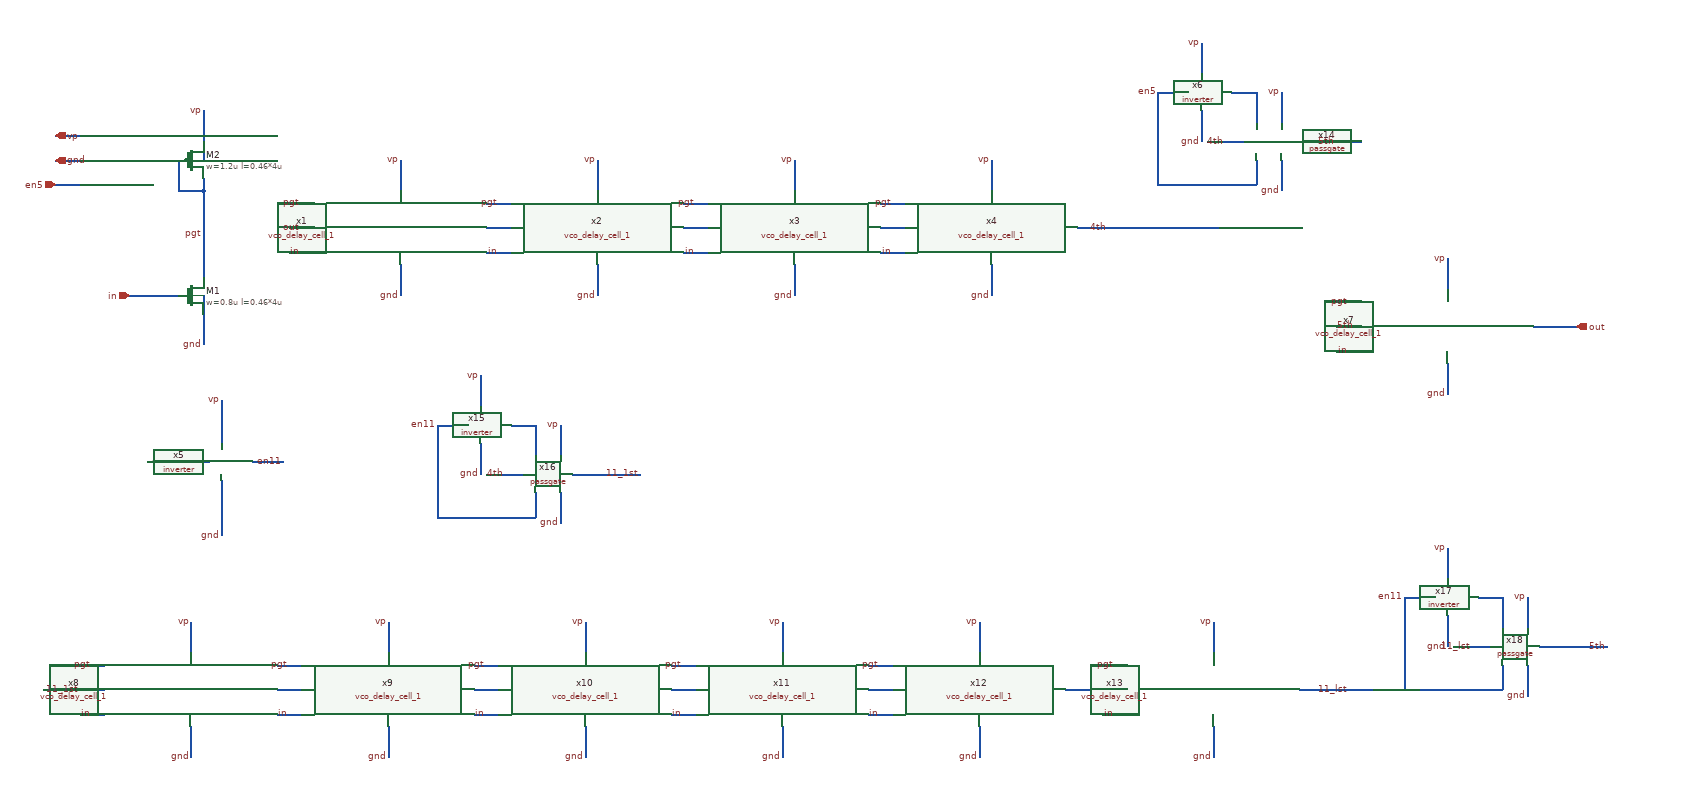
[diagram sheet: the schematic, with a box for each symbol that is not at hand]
v {xschem version=3.4.8RC file_version=1.3}
G {}
K {}
V {}
S {}
F {}
E {}
N -330 -360 -250 -360 {lab=in}
N -250 -530 -210 -530 {lab=pgt}
N -210 -530 -210 -390 {lab=pgt}
N -70 -470 -30 -470 {lab=out}
N -70 -510 -30 -510 {lab=pgt}
N -70 -430 -30 -430 {lab=in}
N 110 -580 110 -530 {lab=vp}
N 110 -410 110 -360 {lab=gnd}
N 250 -510 290 -510 {lab=pgt}
N 250 -430 290 -430 {lab=in}
N 430 -580 430 -530 {lab=vp}
N 430 -410 430 -360 {lab=gnd}
N 570 -510 610 -510 {lab=pgt}
N 570 -430 610 -430 {lab=in}
N 750 -580 750 -530 {lab=vp}
N 750 -410 750 -360 {lab=gnd}
N 890 -510 930 -510 {lab=pgt}
N 890 -430 930 -430 {lab=in}
N 1070 -580 1070 -530 {lab=vp}
N 1070 -410 1070 -360 {lab=gnd}
N -450 -620 -410 -620 {lab=vp}
N -450 -580 -410 -580 {lab=gnd}
N -210 -360 -210 -280 {lab=gnd}
N -250 -580 -250 -530 {lab=pgt}
N -210 -550 -210 -530 {lab=pgt}
N -210 -660 -210 -580 {lab=vp}
N 250 -470 290 -470 {lab=#net1}
N 570 -470 610 -470 {lab=#net2}
N 890 -470 930 -470 {lab=#net3}
N 1630 -350 1670 -350 {lab=pgt}
N 1630 -270 1670 -270 {lab=in}
N 1810 -420 1810 -370 {lab=vp}
N 1810 -250 1810 -200 {lab=gnd}
N 1630 -310 1670 -310 {lab=5th}
N 1950 -310 2020 -310 {lab=out}
N -410 240 -370 240 {lab=pgt}
N -410 320 -370 320 {lab=in}
N -230 170 -230 220 {lab=vp}
N -230 340 -230 390 {lab=gnd}
N -90 240 -50 240 {lab=pgt}
N -90 320 -50 320 {lab=in}
N 90 170 90 220 {lab=vp}
N 90 340 90 390 {lab=gnd}
N 230 240 270 240 {lab=pgt}
N 230 320 270 320 {lab=in}
N 410 170 410 220 {lab=vp}
N 410 340 410 390 {lab=gnd}
N 550 240 590 240 {lab=pgt}
N 550 320 590 320 {lab=in}
N 730 170 730 220 {lab=vp}
N 730 340 730 390 {lab=gnd}
N 870 240 910 240 {lab=pgt}
N 870 320 910 320 {lab=in}
N 1050 170 1050 220 {lab=vp}
N 1050 340 1050 390 {lab=gnd}
N -90 280 -50 280 {lab=#net4}
N 230 280 270 280 {lab=#net5}
N 550 280 590 280 {lab=#net6}
N 870 280 910 280 {lab=#net7}
N 1250 240 1290 240 {lab=pgt}
N 1250 320 1290 320 {lab=in}
N 1430 170 1430 220 {lab=vp}
N 1430 340 1430 390 {lab=gnd}
N 1190 280 1290 280 {lab=#net8}
N 1210 -470 1440 -470 {lab=4th}
N 1570 280 1690 280 {lab=11_lst}
N -470 280 -370 280 {lab=11_1st}
N -450 -540 -410 -540 {lab=en5}
N -300 -90 -200 -90 {lab=en5}
N -130 -90 -80 -90 {lab=en11}
N -180 -60 -180 30 {lab=gnd}
N -180 -190 -180 -120 {lab=vp}
N 1460 -690 1500 -690 {lab=#net9}
N 1500 -690 1500 -640 {lab=#net9}
N 1340 -690 1390 -690 {lab=en5}
N 1340 -690 1340 -540 {lab=en5}
N 1340 -540 1500 -540 {lab=en5}
N 1500 -580 1500 -540 {lab=en5}
N 1420 -610 1480 -610 {lab=4th}
N 1560 -610 1670 -610 {lab=5th}
N 1410 -770 1410 -720 {lab=vp}
N 1410 -660 1410 -610 {lab=gnd}
N 1540 -580 1540 -530 {lab=gnd}
N 1540 -690 1540 -640 {lab=vp}
N 290 -150 330 -150 {lab=#net10}
N 330 -150 330 -100 {lab=#net10}
N 170 -150 220 -150 {lab=en11}
N 170 -150 170 0 {lab=en11}
N 170 0 330 0 {lab=en11}
N 330 -40 330 0 {lab=en11}
N 250 -70 310 -70 {lab=4th}
N 390 -70 500 -70 {lab=11_1st}
N 240 -230 240 -180 {lab=vp}
N 240 -120 240 -70 {lab=gnd}
N 370 -40 370 10 {lab=gnd}
N 370 -150 370 -100 {lab=vp}
N 1860 130 1900 130 {lab=#net11}
N 1900 130 1900 180 {lab=#net11}
N 1740 130 1790 130 {lab=en11}
N 1740 130 1740 280 {lab=en11}
N 1740 280 1900 280 {lab=en11}
N 1900 240 1900 280 {lab=en11}
N 1820 210 1880 210 {lab=11_lst}
N 1960 210 2070 210 {lab=11_1st}
N 1810 50 1810 100 {lab=vp}
N 1810 160 1810 210 {lab=gnd}
N 1940 240 1940 290 {lab=gnd}
N 1940 130 1940 180 {lab=vp}
C {sg13g2_pr/sg13_lv_nmos.sym} -230 -360 0 0 {name=M1
l=0.46*4u
w=0.8u
ng=1
m=1
model=sg13_lv_nmos
spiceprefix=X
}
C {sg13g2_pr/sg13_lv_pmos.sym} -230 -580 0 0 {name=M2
l=0.46*4u
w=1.2u
ng=1
m=1
model=sg13_lv_pmos
spiceprefix=X
}
C {ipin.sym} -330 -360 0 0 {name=p1 lab=in}
C {iopin.sym} -450 -620 0 1 {name=p3 lab=vp
}
C {opin.sym} 2020 -310 0 0 {name=p4 lab=out}
C {/foss/designs/CHIP-PLL/schematics/vco/vco_cell/vco_delay_cell_1.sym} 110 -470 0 0 {name=x1}
C {lab_wire.sym} -50 -470 0 0 {name=p5 sig_type=std_logic lab=out
}
C {lab_wire.sym} -50 -510 0 0 {name=p10 sig_type=std_logic lab=pgt
}
C {lab_wire.sym} -50 -430 0 0 {name=p11 sig_type=std_logic lab=in
}
C {lab_wire.sym} -210 -660 0 0 {name=p12 sig_type=std_logic lab=vp
}
C {lab_wire.sym} 110 -580 0 0 {name=p13 sig_type=std_logic lab=vp
}
C {lab_wire.sym} 110 -360 0 0 {name=p15 sig_type=std_logic lab=gnd
}
C {/foss/designs/CHIP-PLL/schematics/vco/vco_cell/vco_delay_cell_1.sym} 430 -470 0 0 {name=x2}
C {lab_wire.sym} 270 -510 0 0 {name=p7 sig_type=std_logic lab=pgt
}
C {lab_wire.sym} 270 -430 0 0 {name=p8 sig_type=std_logic lab=in
}
C {lab_wire.sym} 430 -580 0 0 {name=p9 sig_type=std_logic lab=vp
}
C {lab_wire.sym} 430 -360 0 0 {name=p16 sig_type=std_logic lab=gnd
}
C {/foss/designs/CHIP-PLL/schematics/vco/vco_cell/vco_delay_cell_1.sym} 750 -470 0 0 {name=x3}
C {lab_wire.sym} 590 -510 0 0 {name=p18 sig_type=std_logic lab=pgt
}
C {lab_wire.sym} 590 -430 0 0 {name=p19 sig_type=std_logic lab=in
}
C {lab_wire.sym} 750 -580 0 0 {name=p20 sig_type=std_logic lab=vp
}
C {lab_wire.sym} 750 -360 0 0 {name=p21 sig_type=std_logic lab=gnd
}
C {/foss/designs/CHIP-PLL/schematics/vco/vco_cell/vco_delay_cell_1.sym} 1070 -470 0 0 {name=x4}
C {lab_wire.sym} 910 -510 0 0 {name=p23 sig_type=std_logic lab=pgt
}
C {lab_wire.sym} 910 -430 0 0 {name=p24 sig_type=std_logic lab=in
}
C {lab_wire.sym} 1070 -580 0 0 {name=p25 sig_type=std_logic lab=vp
}
C {lab_wire.sym} 1070 -360 0 0 {name=p26 sig_type=std_logic lab=gnd
}
C {iopin.sym} -450 -580 0 1 {name=p32 lab=gnd}
C {lab_wire.sym} -210 -280 0 0 {name=p2 sig_type=std_logic lab=gnd
}
C {lab_wire.sym} -210 -460 0 0 {name=p14 sig_type=std_logic lab=pgt
}
C {/foss/designs/CHIP-PLL/schematics/vco/vco_cell/vco_delay_cell_1.sym} 1810 -310 0 0 {name=x7}
C {lab_wire.sym} 1650 -350 0 0 {name=p39 sig_type=std_logic lab=pgt
}
C {lab_wire.sym} 1650 -270 0 0 {name=p40 sig_type=std_logic lab=in
}
C {lab_wire.sym} 1810 -420 0 0 {name=p41 sig_type=std_logic lab=vp
}
C {lab_wire.sym} 1810 -200 0 0 {name=p42 sig_type=std_logic lab=gnd
}
C {/foss/designs/CHIP-PLL/schematics/vco/vco_cell/vco_delay_cell_1.sym} -230 280 0 0 {name=x8}
C {lab_wire.sym} -390 240 0 0 {name=p17 sig_type=std_logic lab=pgt
}
C {lab_wire.sym} -390 320 0 0 {name=p22 sig_type=std_logic lab=in
}
C {lab_wire.sym} -230 170 0 0 {name=p27 sig_type=std_logic lab=vp
}
C {lab_wire.sym} -230 390 0 0 {name=p33 sig_type=std_logic lab=gnd
}
C {/foss/designs/CHIP-PLL/schematics/vco/vco_cell/vco_delay_cell_1.sym} 90 280 0 0 {name=x9}
C {lab_wire.sym} -70 240 0 0 {name=p38 sig_type=std_logic lab=pgt
}
C {lab_wire.sym} -70 320 0 0 {name=p43 sig_type=std_logic lab=in
}
C {lab_wire.sym} 90 170 0 0 {name=p44 sig_type=std_logic lab=vp
}
C {lab_wire.sym} 90 390 0 0 {name=p45 sig_type=std_logic lab=gnd
}
C {/foss/designs/CHIP-PLL/schematics/vco/vco_cell/vco_delay_cell_1.sym} 410 280 0 0 {name=x10}
C {lab_wire.sym} 250 240 0 0 {name=p46 sig_type=std_logic lab=pgt
}
C {lab_wire.sym} 250 320 0 0 {name=p47 sig_type=std_logic lab=in
}
C {lab_wire.sym} 410 170 0 0 {name=p48 sig_type=std_logic lab=vp
}
C {lab_wire.sym} 410 390 0 0 {name=p49 sig_type=std_logic lab=gnd
}
C {/foss/designs/CHIP-PLL/schematics/vco/vco_cell/vco_delay_cell_1.sym} 730 280 0 0 {name=x11}
C {lab_wire.sym} 570 240 0 0 {name=p50 sig_type=std_logic lab=pgt
}
C {lab_wire.sym} 570 320 0 0 {name=p51 sig_type=std_logic lab=in
}
C {lab_wire.sym} 730 170 0 0 {name=p52 sig_type=std_logic lab=vp
}
C {lab_wire.sym} 730 390 0 0 {name=p53 sig_type=std_logic lab=gnd
}
C {/foss/designs/CHIP-PLL/schematics/vco/vco_cell/vco_delay_cell_1.sym} 1050 280 0 0 {name=x12}
C {lab_wire.sym} 890 240 0 0 {name=p54 sig_type=std_logic lab=pgt
}
C {lab_wire.sym} 890 320 0 0 {name=p55 sig_type=std_logic lab=in
}
C {lab_wire.sym} 1050 170 0 0 {name=p56 sig_type=std_logic lab=vp
}
C {lab_wire.sym} 1050 390 0 0 {name=p57 sig_type=std_logic lab=gnd
}
C {/foss/designs/CHIP-PLL/schematics/vco/vco_cell/vco_delay_cell_1.sym} 1430 280 0 0 {name=x13}
C {lab_wire.sym} 1270 240 0 0 {name=p58 sig_type=std_logic lab=pgt
}
C {lab_wire.sym} 1270 320 0 0 {name=p59 sig_type=std_logic lab=in
}
C {lab_wire.sym} 1430 170 0 0 {name=p60 sig_type=std_logic lab=vp
}
C {lab_wire.sym} 1430 390 0 0 {name=p61 sig_type=std_logic lab=gnd
}
C {lab_wire.sym} 1260 -470 0 0 {name=p6 sig_type=std_logic lab=4th
}
C {lab_wire.sym} 1660 -310 0 0 {name=p36 sig_type=std_logic lab=5th
}
C {lab_wire.sym} -410 280 0 0 {name=p64 sig_type=std_logic lab=11_1st
}
C {lab_wire.sym} -260 -90 0 0 {name=p66 sig_type=std_logic lab=en5
}
C {lab_wire.sym} -180 -190 0 0 {name=p67 sig_type=std_logic lab=vp
}
C {lab_wire.sym} -180 30 0 0 {name=p68 sig_type=std_logic lab=gnd
}
C {lab_wire.sym} -80 -90 0 0 {name=p69 sig_type=std_logic lab=en11
}
C {ipin.sym} -450 -540 0 0 {name=p70 lab=en5}
C {/foss/designs/CHIP-PLL/schematics/divider/schematics/inverter.sym} -180 -90 0 0 {name=x5}
C {/foss/designs/CHIP-PLL/schematics/divider/schematics/inverter.sym} 1410 -690 0 0 {name=x6}
C {/foss/designs/CHIP-PLL/schematics/divider/schematics/passgate.sym} 1500 -590 0 0 {name=x14}
C {lab_wire.sym} 1340 -690 0 0 {name=p65 sig_type=std_logic lab=en5
}
C {lab_wire.sym} 1450 -610 0 0 {name=p71 sig_type=std_logic lab=4th
}
C {lab_wire.sym} 1630 -610 0 0 {name=p72 sig_type=std_logic lab=5th
}
C {lab_wire.sym} 1410 -770 0 0 {name=p73 sig_type=std_logic lab=vp
}
C {lab_wire.sym} 1410 -610 0 0 {name=p74 sig_type=std_logic lab=gnd
}
C {lab_wire.sym} 1540 -530 0 0 {name=p75 sig_type=std_logic lab=gnd
}
C {lab_wire.sym} 1540 -690 0 0 {name=p76 sig_type=std_logic lab=vp
}
C {/foss/designs/CHIP-PLL/schematics/divider/schematics/inverter.sym} 240 -150 0 0 {name=x15}
C {/foss/designs/CHIP-PLL/schematics/divider/schematics/passgate.sym} 330 -50 0 0 {name=x16}
C {lab_wire.sym} 170 -150 0 0 {name=p28 sig_type=std_logic lab=en11
}
C {lab_wire.sym} 280 -70 0 0 {name=p29 sig_type=std_logic lab=4th
}
C {lab_wire.sym} 240 -230 0 0 {name=p77 sig_type=std_logic lab=vp
}
C {lab_wire.sym} 240 -70 0 0 {name=p78 sig_type=std_logic lab=gnd
}
C {lab_wire.sym} 370 10 0 0 {name=p79 sig_type=std_logic lab=gnd
}
C {lab_wire.sym} 370 -150 0 0 {name=p80 sig_type=std_logic lab=vp
}
C {lab_wire.sym} 500 -70 0 0 {name=p81 sig_type=std_logic lab=11_1st
}
C {lab_wire.sym} 1650 280 0 0 {name=p30 sig_type=std_logic lab=11_lst
}
C {/foss/designs/CHIP-PLL/schematics/divider/schematics/inverter.sym} 1810 130 0 0 {name=x17}
C {/foss/designs/CHIP-PLL/schematics/divider/schematics/passgate.sym} 1900 230 0 0 {name=x18}
C {lab_wire.sym} 1740 130 0 0 {name=p31 sig_type=std_logic lab=en11
}
C {lab_wire.sym} 1850 210 0 0 {name=p34 sig_type=std_logic lab=11_lst
}
C {lab_wire.sym} 1810 50 0 0 {name=p35 sig_type=std_logic lab=vp
}
C {lab_wire.sym} 1810 210 0 0 {name=p82 sig_type=std_logic lab=gnd
}
C {lab_wire.sym} 1940 290 0 0 {name=p83 sig_type=std_logic lab=gnd
}
C {lab_wire.sym} 1940 130 0 0 {name=p84 sig_type=std_logic lab=vp
}
C {lab_wire.sym} 2070 210 0 0 {name=p85 sig_type=std_logic lab=5th
}
